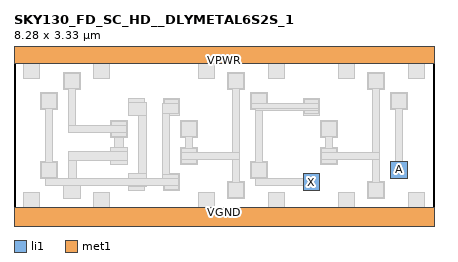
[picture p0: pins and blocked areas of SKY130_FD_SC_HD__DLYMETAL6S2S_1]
MACRO SKY130_FD_SC_HD__DLYMETAL6S2S_1
 CLASS CORE ;
 FOREIGN SKY130_FD_SC_HD__DLYMETAL6S2S_1 0 0 ;
 SIZE 8.28 BY 3.33 ;
 ORIGIN 0 0 ;
 SYMMETRY X Y R90 ;
 SITE unit ;
  PIN VPWR
   DIRECTION INOUT ;
   USE POWER ;
   SHAPE ABUTMENT ;
    PORT
     CLASS CORE ;
       LAYER li1 ;
        RECT 0.00000000 3.09000000 8.28000000 3.57000000 ;
       LAYER met1 ;
        RECT 0.00000000 3.09000000 8.28000000 3.57000000 ;
    END
  END VPWR

  PIN VGND
   DIRECTION INOUT ;
   USE POWER ;
   SHAPE ABUTMENT ;
    PORT
     CLASS CORE ;
       LAYER li1 ;
        RECT 0.00000000 -0.24000000 8.28000000 0.24000000 ;
       LAYER met1 ;
        RECT 0.00000000 -0.24000000 8.28000000 0.24000000 ;
    END
  END VGND

  PIN X
   DIRECTION INOUT ;
   USE SIGNAL ;
   SHAPE ABUTMENT ;
    PORT
     CLASS CORE ;
       LAYER li1 ;
        RECT 5.70000000 0.58000000 6.03000000 0.91000000 ;
    END
  END X

  PIN A
   DIRECTION INOUT ;
   USE SIGNAL ;
   SHAPE ABUTMENT ;
    PORT
     CLASS CORE ;
       LAYER li1 ;
        RECT 7.42500000 0.82500000 7.75500000 1.15500000 ;
    END
  END A

 OBS
    LAYER polycont ;
     RECT 6.12500000 1.17500000 6.29500000 1.34500000 ;
     RECT 6.12500000 1.71500000 6.29500000 1.88500000 ;
     RECT 0.60500000 0.90500000 0.77500000 1.07500000 ;
     RECT 0.60500000 2.25500000 0.77500000 2.42500000 ;
     RECT 3.36500000 1.17500000 3.53500000 1.34500000 ;
     RECT 3.36500000 1.71500000 3.53500000 1.88500000 ;
     RECT 7.50500000 0.90500000 7.67500000 1.07500000 ;
     RECT 7.50500000 2.25500000 7.67500000 2.42500000 ;
     RECT 1.98500000 1.17500000 2.15500000 1.34500000 ;
     RECT 1.98500000 1.71500000 2.15500000 1.88500000 ;
     RECT 4.74500000 0.90500000 4.91500000 1.07500000 ;
     RECT 4.74500000 2.25500000 4.91500000 2.42500000 ;

    LAYER pdiffc ;
     RECT 7.04500000 2.66000000 7.21500000 2.83000000 ;
     RECT 0.26000000 2.86000000 0.43000000 3.03000000 ;
     RECT 1.64000000 2.86000000 1.81000000 3.03000000 ;
     RECT 3.71000000 2.86000000 3.88000000 3.03000000 ;
     RECT 5.09000000 2.86000000 5.26000000 3.03000000 ;
     RECT 6.47000000 2.86000000 6.64000000 3.03000000 ;
     RECT 7.85000000 2.86000000 8.02000000 3.03000000 ;
     RECT 3.02000000 2.15000000 3.19000000 2.32000000 ;
     RECT 4.28500000 2.66000000 4.45500000 2.83000000 ;
     RECT 1.06500000 2.66000000 1.23500000 2.83000000 ;
     RECT 5.78000000 2.15000000 5.95000000 2.32000000 ;
     RECT 2.33000000 2.15000000 2.50000000 2.32000000 ;

    LAYER ndiffc ;
     RECT 7.04500000 0.50000000 7.21500000 0.67000000 ;
     RECT 3.02000000 0.66000000 3.19000000 0.83000000 ;
     RECT 4.28500000 0.50000000 4.45500000 0.67000000 ;
     RECT 0.26000000 0.30000000 0.43000000 0.47000000 ;
     RECT 1.64000000 0.30000000 1.81000000 0.47000000 ;
     RECT 3.71000000 0.30000000 3.88000000 0.47000000 ;
     RECT 5.09000000 0.30000000 5.26000000 0.47000000 ;
     RECT 6.47000000 0.30000000 6.64000000 0.47000000 ;
     RECT 7.85000000 0.30000000 8.02000000 0.47000000 ;
     RECT 1.06500000 0.50000000 1.23500000 0.67000000 ;
     RECT 5.78000000 0.66000000 5.95000000 0.83000000 ;
     RECT 2.33000000 0.66000000 2.50000000 0.83000000 ;

    LAYER li1 ;
     RECT 6.96500000 0.42000000 7.29500000 0.75000000 ;
     RECT 6.04500000 1.09500000 6.37500000 1.42500000 ;
     RECT 6.04500000 1.63500000 6.37500000 1.96500000 ;
     RECT 6.96500000 2.58000000 7.29500000 2.91000000 ;
     RECT 0.18000000 2.78000000 0.51000000 3.09000000 ;
     RECT 1.56000000 2.78000000 1.89000000 3.09000000 ;
     RECT 3.63000000 2.78000000 3.96000000 3.09000000 ;
     RECT 5.01000000 2.78000000 5.34000000 3.09000000 ;
     RECT 6.39000000 2.78000000 6.72000000 3.09000000 ;
     RECT 7.77000000 2.78000000 8.10000000 3.09000000 ;
     RECT 0.00000000 3.09000000 8.28000000 3.57000000 ;
     RECT 2.94000000 0.58000000 3.27000000 0.91000000 ;
     RECT 0.52500000 0.82500000 0.85500000 1.15500000 ;
     RECT 2.94000000 2.07000000 3.27000000 2.40000000 ;
     RECT 0.52500000 2.17500000 0.85500000 2.50500000 ;
     RECT 4.20500000 0.42000000 4.53500000 0.75000000 ;
     RECT 3.28500000 1.09500000 3.61500000 1.42500000 ;
     RECT 3.28500000 1.63500000 3.61500000 1.96500000 ;
     RECT 4.20500000 2.58000000 4.53500000 2.91000000 ;
     RECT 0.00000000 -0.24000000 8.28000000 0.24000000 ;
     RECT 0.18000000 0.24000000 0.51000000 0.55000000 ;
     RECT 1.56000000 0.24000000 1.89000000 0.55000000 ;
     RECT 3.63000000 0.24000000 3.96000000 0.55000000 ;
     RECT 5.01000000 0.24000000 5.34000000 0.55000000 ;
     RECT 6.39000000 0.24000000 6.72000000 0.55000000 ;
     RECT 7.77000000 0.24000000 8.10000000 0.55000000 ;
     RECT 7.42500000 0.82500000 7.75500000 1.15500000 ;
     RECT 7.42500000 2.17500000 7.75500000 2.50500000 ;
     RECT 0.98500000 0.42000000 1.31500000 0.75000000 ;
     RECT 1.06500000 0.75000000 1.23500000 1.17500000 ;
     RECT 1.90500000 1.09500000 2.23500000 1.17500000 ;
     RECT 1.06500000 1.17500000 2.23500000 1.34500000 ;
     RECT 1.90500000 1.34500000 2.23500000 1.42500000 ;
     RECT 1.98500000 1.42500000 2.15500000 1.63500000 ;
     RECT 1.90500000 1.63500000 2.23500000 1.96500000 ;
     RECT 0.98500000 2.58000000 1.31500000 2.91000000 ;
     RECT 5.70000000 0.58000000 6.03000000 0.91000000 ;
     RECT 4.66500000 0.82500000 4.99500000 1.15500000 ;
     RECT 5.70000000 2.07000000 6.03000000 2.40000000 ;
     RECT 4.66500000 2.17500000 4.99500000 2.50500000 ;
     RECT 2.25000000 0.58000000 2.58000000 0.66000000 ;
     RECT 2.25000000 0.66000000 2.61500000 0.91000000 ;
     RECT 2.44500000 0.91000000 2.61500000 2.07000000 ;
     RECT 2.25000000 2.07000000 2.61500000 2.32000000 ;
     RECT 2.25000000 2.32000000 2.58000000 2.40000000 ;

    LAYER viali ;
     RECT 7.04500000 0.50000000 7.21500000 0.67000000 ;
     RECT 6.12500000 1.17500000 6.29500000 1.34500000 ;
     RECT 6.12500000 1.71500000 6.29500000 1.88500000 ;
     RECT 7.04500000 2.66000000 7.21500000 2.83000000 ;
     RECT 7.85000000 3.24500000 8.02000000 3.41500000 ;
     RECT 3.02000000 0.66000000 3.19000000 0.83000000 ;
     RECT 0.60500000 0.90500000 0.77500000 1.07500000 ;
     RECT 3.02000000 2.15000000 3.19000000 2.32000000 ;
     RECT 0.60500000 2.25500000 0.77500000 2.42500000 ;
     RECT 4.28500000 0.50000000 4.45500000 0.67000000 ;
     RECT 3.36500000 1.17500000 3.53500000 1.34500000 ;
     RECT 3.36500000 1.71500000 3.53500000 1.88500000 ;
     RECT 4.28500000 2.66000000 4.45500000 2.83000000 ;
     RECT 7.85000000 -0.08500000 8.02000000 0.08500000 ;
     RECT 7.50500000 0.90500000 7.67500000 1.07500000 ;
     RECT 7.50500000 2.25500000 7.67500000 2.42500000 ;
     RECT 1.98500000 1.71500000 2.15500000 1.88500000 ;
     RECT 1.06500000 2.66000000 1.23500000 2.83000000 ;
     RECT 5.78000000 0.66000000 5.95000000 0.83000000 ;
     RECT 4.74500000 0.90500000 4.91500000 1.07500000 ;
     RECT 5.78000000 2.15000000 5.95000000 2.32000000 ;
     RECT 4.74500000 2.25500000 4.91500000 2.42500000 ;

    LAYER met1 ;
     RECT 0.76000000 0.81500000 0.83500000 0.84500000 ;
     RECT 4.90000000 0.81500000 4.97500000 0.84500000 ;
     RECT 6.98500000 0.44000000 7.27500000 0.73000000 ;
     RECT 6.06500000 1.11500000 6.35500000 1.19000000 ;
     RECT 7.06000000 0.73000000 7.20000000 1.19000000 ;
     RECT 6.06500000 1.19000000 7.20000000 1.33000000 ;
     RECT 6.06500000 1.33000000 6.35500000 1.40500000 ;
     RECT 6.14000000 1.40500000 6.28000000 1.65500000 ;
     RECT 6.06500000 1.65500000 6.35500000 1.94500000 ;
     RECT 7.06000000 1.33000000 7.20000000 2.60000000 ;
     RECT 6.98500000 2.60000000 7.27500000 2.89000000 ;
     RECT 0.00000000 3.09000000 8.28000000 3.57000000 ;
     RECT 2.96000000 0.60000000 3.25000000 0.67500000 ;
     RECT 0.62000000 0.67500000 3.25000000 0.81500000 ;
     RECT 0.62000000 0.81500000 0.76000000 0.84500000 ;
     RECT 2.92000000 0.81500000 3.25000000 0.89000000 ;
     RECT 0.54500000 0.84500000 0.83500000 1.13500000 ;
     RECT 2.92000000 0.89000000 3.06000000 2.09000000 ;
     RECT 0.62000000 1.13500000 0.76000000 2.19500000 ;
     RECT 2.92000000 2.09000000 3.25000000 2.30500000 ;
     RECT 2.96000000 2.30500000 3.25000000 2.38000000 ;
     RECT 0.54500000 2.19500000 0.83500000 2.48500000 ;
     RECT 4.22500000 0.44000000 4.51500000 0.73000000 ;
     RECT 3.30500000 1.11500000 3.59500000 1.19000000 ;
     RECT 4.30000000 0.73000000 4.44000000 1.19000000 ;
     RECT 3.30500000 1.19000000 4.44000000 1.33000000 ;
     RECT 3.30500000 1.33000000 3.59500000 1.40500000 ;
     RECT 3.38000000 1.40500000 3.52000000 1.65500000 ;
     RECT 3.30500000 1.65500000 3.59500000 1.94500000 ;
     RECT 4.30000000 1.33000000 4.44000000 2.60000000 ;
     RECT 4.22500000 2.60000000 4.51500000 2.89000000 ;
     RECT 0.00000000 -0.24000000 8.28000000 0.24000000 ;
     RECT 7.44500000 0.84500000 7.73500000 1.13500000 ;
     RECT 7.52000000 1.13500000 7.66000000 2.19500000 ;
     RECT 7.44500000 2.19500000 7.73500000 2.48500000 ;
     RECT 1.92500000 1.65500000 2.21500000 1.73000000 ;
     RECT 1.08000000 1.73000000 2.21500000 1.87000000 ;
     RECT 1.92500000 1.87000000 2.21500000 1.94500000 ;
     RECT 1.08000000 1.87000000 1.22000000 2.60000000 ;
     RECT 1.00500000 2.60000000 1.29500000 2.89000000 ;
     RECT 5.72000000 0.60000000 6.01000000 0.67500000 ;
     RECT 4.76000000 0.67500000 6.01000000 0.81500000 ;
     RECT 4.76000000 0.81500000 4.90000000 0.84500000 ;
     RECT 5.72000000 0.81500000 6.01000000 0.89000000 ;
     RECT 4.68500000 0.84500000 4.97500000 1.13500000 ;
     RECT 4.76000000 1.13500000 4.90000000 2.16500000 ;
     RECT 5.72000000 2.09000000 6.01000000 2.16500000 ;
     RECT 4.76000000 2.16500000 6.01000000 2.19500000 ;
     RECT 4.68500000 2.19500000 6.01000000 2.30500000 ;
     RECT 5.72000000 2.30500000 6.01000000 2.38000000 ;
     RECT 4.68500000 2.30500000 4.97500000 2.48500000 ;

    LAYER via ;


    LAYER met2 ;


    LAYER via2 ;


    LAYER met3 ;


 END
END SKY130_FD_SC_HD__DLYMETAL6S2S_1
